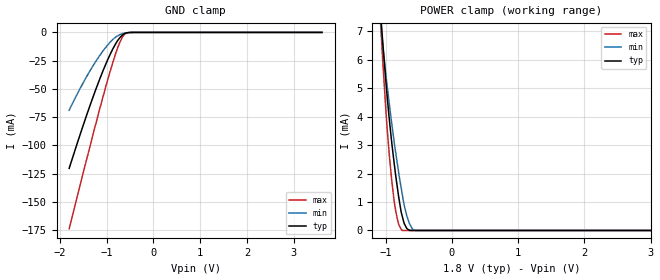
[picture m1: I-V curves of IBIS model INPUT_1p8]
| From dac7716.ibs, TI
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|   input_1p8 Model
[Model]   INPUT_1p8
Model_type   Input
Vinl = 0.2
Vinh = 1.6
|   typ   min   max
|   (nom PVT)   (Fast PVT)   (slow PVT)
|Average
C_comp   3.106e-12   2.398e-12   3.692e-12
[Voltage Range]   1.8   1.7   1.9
|Ambient Temperature   25   105   -40
|Junction Temperature
[Temperature Range]   42   122   -40
[Power Clamp Reference]   1.8   1.7   1.9
[GND Clamp Reference]   0   0   0
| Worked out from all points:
|   GND clamp passes 1 mA (typ) near -0.61 V on its own axis
|   POWER clamp passes 1 mA (typ) near -0.79 V on its own axis
[GND Clamp]
|   Voltage   I(typ)   I(min)   I(max)
-1.8V     -120.4mA   -68.92mA   -173.7mA
-1.581V   -92.27mA   -50.8mA    -137.6mA
-1.392V   -69.11mA   -36.58mA   -106.8mA
-1.231V   -50.47mA   -25.64mA   -80.95mA
-1.071V   -33.33mA   -16.04mA   -56mA
-874.8mV  -15.17mA   -6.608mA   -27.58mA
-764.5mV  -7.199mA   -3.024mA   -13.6mA
-663.8mV  -2.384mA   -1.099mA   -4.149mA
-608.7mV  -920.7uA   -595.9uA   -1.426mA
-546mV    -275.9uA   -244.2uA   -155.3uA
-480.6mV  0A         -160.9uA   0A
3.6V      0A         0A         0A
[POWER Clamp]
|   Voltage   I(typ)   I(min)   I(max)
-1.8V     35.79mA    30.17mA    43.21mA
-1.085V   7.869mA    7.535mA    7.588mA
-1.05V    6.752mA    6.637mA    6.143mA
-983mV    4.836mA    5.181mA    3.724mA
-910.8mV  3.126mA    3.786mA    1.798mA
-842.4mV  1.812mA    2.629mA    600.1uA
-804.4mV  1.187mA    2.034mA    219uA
-751.2mV  510.1uA    1.288mA    0A
-720mV    241.6uA    877.8uA    0A
-642.3mV  7.716uA    248.3uA    0A
-550.8mV  0A         0A         0A
3.6V      0A         0A         0A
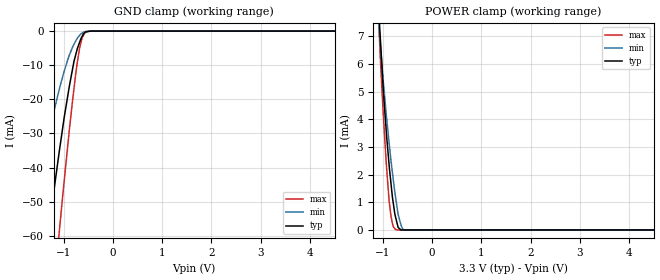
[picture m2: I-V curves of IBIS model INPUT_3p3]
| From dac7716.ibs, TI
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|   input_3p3 Model
[Model]   INPUT_3p3
Model_type   Input
Vinl = 0.6
Vinh = 2.1
|   typ   min   max
|   (nom PVT)   (Fast PVT)   (slow PVT)
|Average
C_comp   2.757e-12   2.145e-12   3.258e-12
[Voltage Range]   3.3   3   3.6
|Ambient Temperature   25   105   -40
|Junction Temperature
[Temperature Range]   42   122   -40
[Power Clamp Reference]   3.3   3   3.6
[GND Clamp Reference]   0   0   0
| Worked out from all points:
|   GND clamp passes 1 mA (typ) near -0.60 V on its own axis
|   POWER clamp passes 1 mA (typ) near -0.79 V on its own axis
[GND Clamp]
|   Voltage   I(typ)   I(min)   I(max)
-3.3V     -325.7mA   -216.2mA   -421.2mA
-1.71V    -108.7mA   -61.27mA   -158.8mA
-1.614V   -96.39mA   -53.51mA   -143mA
-1.34V    -62.93mA   -32.99mA   -98.35mA
-1.29V    -57.27mA   -29.5mA    -90.41mA
-1.092V   -35.57mA   -17.27mA   -59.26mA
-887.7mV  -16.4mA    -7.12mA    -29.36mA
-754.8mV  -6.89mA    -2.912mA   -12.47mA
-675.6mV  -3.238mA   -1.267mA   -4.935mA
-594mV    -727.4uA   -292.2uA   -1.154mA
-463.2mV  -25.21uA   -32.29uA   0A
6.6V      0A         0A         0A
[POWER Clamp]
|   Voltage   I(typ)   I(min)   I(max)
-3.3V     98.4mA     82.08mA    122mA
-1.076V   7.67mA     7.298mA    7.188mA
-1.054V   6.983mA    6.758mA    6.298mA
-996mV    5.198mA    5.464mA    4.313mA
-934.8mV  3.656mA    4.246mA    2.524mA
-873.6mV  2.352mA    3.163mA    1.066mA
-805.2mV  1.172mA    2.064mA    225.3uA
-759mV    604.9uA    1.39mA     48.88uA
-715.2mV  270.7uA    860.8uA    0A
-627mV    0A         150.6uA    0A
-543mV    0A         0A         0A
6.6V      0A         0A         0A
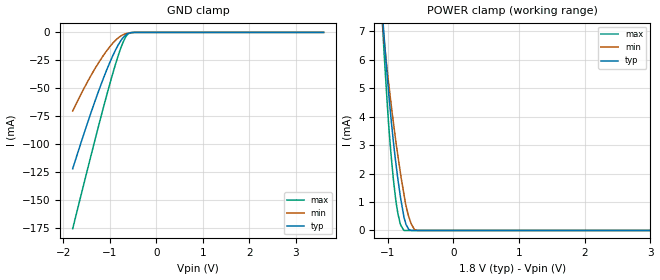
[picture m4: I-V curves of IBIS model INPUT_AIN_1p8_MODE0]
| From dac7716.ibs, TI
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|   input_ain_1p8_mode0 Model
[Model]   INPUT_AIN_1p8_MODE0
Model_type   Input
Vinl = 0.2
Vinh = 1.6
|   typ   min   max
|   (nom PVT)   (Fast PVT)   (slow PVT)
|Average
C_comp   3.175e-12   2.467e-12   3.761e-12
[Voltage Range]   1.8   1.7   1.9
|Ambient Temperature   25   105   -40
|Junction Temperature
[Temperature Range]   42   122   -40
[Power Clamp Reference]   1.8   1.7   1.9
[GND Clamp Reference]   0   0   0
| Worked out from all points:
|   GND clamp passes 1 mA (typ) near -0.61 V on its own axis
|   POWER clamp passes 1 mA (typ) near -0.79 V on its own axis
[GND Clamp]
|   Voltage   I(typ)   I(min)   I(max)
-1.8V     -122mA     -70.37mA   -175.7mA
-1.581V   -93.56mA   -51.97mA   -139.1mA
-1.402V   -71.32mA   -38.27mA   -109.6mA
-1.226V   -50.61mA   -26.04mA   -80.96mA
-1.067V   -33.48mA   -16.39mA   -56.1mA
-882mV    -16.06mA   -7.204mA   -28.95mA
-764.5mV  -7.408mA   -3.214mA   -13.83mA
-661.9mV  -2.445mA   -1.173mA   -4.111mA
-606.8mV  -916.4uA   -640.6uA   -1.426mA
-544.1mV  -240.9uA   -258.5uA   -159.5uA
-466.2mV  0A         0A         0A
3.6V      0A         0A         0A
[POWER Clamp]
|   Voltage   I(typ)   I(min)   I(max)
-1.8V     35.79mA    30.17mA    43.21mA
-1.073V   7.453mA    7.22mA     7.082mA
-1.049V   6.705mA    6.615mA    6.109mA
-983mV    4.848mA    5.181mA    3.724mA
-910.8mV  3.123mA    3.796mA    1.798mA
-842.4mV  1.81mA     2.629mA    600.1uA
-804.4mV  1.197mA    2.034mA    219uA
-751.2mV  486.1uA    1.288mA    0A
-716.4mV  200.3uA    843.9uA    0A
-642.3mV  1.727uA    248.3uA    0A
-543.7mV  0A         0A         0A
3.6V      0A         0A         0A
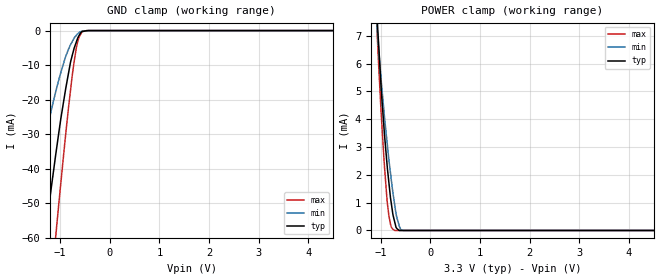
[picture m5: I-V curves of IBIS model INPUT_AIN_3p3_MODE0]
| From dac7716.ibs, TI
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|   input_ain_3p3_mode0 Model
[Model]   INPUT_AIN_3p3_MODE0
Model_type   Input
Vinl = 0.6
Vinh = 2.1
|   typ   min   max
|   (nom PVT)   (Fast PVT)   (slow PVT)
|Average
C_comp   2.821e-12   2.209e-12   3.322e-12
[Voltage Range]   3.3   3   3.6
|Ambient Temperature   25   105   -40
|Junction Temperature
[Temperature Range]   42   122   -40
[Power Clamp Reference]   3.3   3   3.6
[GND Clamp Reference]   0   0   0
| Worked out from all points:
|   GND clamp passes 1 mA (typ) near -0.60 V on its own axis
|   POWER clamp passes 1 mA (typ) near -0.79 V on its own axis
[GND Clamp]
|   Voltage   I(typ)   I(min)   I(max)
-3.3V     -329.7mA   -219.5mA   -426.2mA
-1.704V   -109.5mA   -62.1mA    -159.6mA
-1.607V   -96.89mA   -54.17mA   -143.5mA
-1.284V   -57.42mA   -29.91mA   -90.33mA
-1.092V   -36.12mA   -17.84mA   -59.93mA
-1.068V   -33.64mA   -16.42mA   -56.15mA
-887.7mV  -16.69mA   -7.449mA   -29.8mA
-754.8mV  -7.061mA   -3.116mA   -12.69mA
-675.6mV  -3.33mA    -1.382mA   -5.06mA
-591mV    -733.5uA   -327.4uA   -1.128mA
-463.2mV  -29.3uA    -42.59uA   0A
6.6V      0A         0A         0A
[POWER Clamp]
|   Voltage   I(typ)   I(min)   I(max)
-3.3V     98.4mA     82.08mA    122mA
-1.076V   7.67mA     7.298mA    7.188mA
-1.054V   6.983mA    6.758mA    6.299mA
-992.4mV  5.087mA    5.388mA    4.199mA
-934.8mV  3.651mA    4.246mA    2.524mA
-873.6mV  2.352mA    3.163mA    1.066mA
-805.2mV  1.172mA    2.064mA    225.5uA
-759mV    604.9uA    1.39mA     48.9uA
-715.2mV  270.8uA    860.8uA    0A
-627mV    0A         150.6uA    0A
-543mV    0A         0A         0A
6.6V      0A         0A         0A
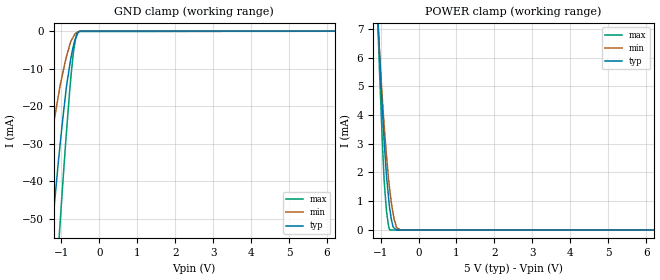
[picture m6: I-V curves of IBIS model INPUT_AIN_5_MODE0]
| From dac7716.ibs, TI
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|   input_ain_5_mode0 Model
[Model]   INPUT_AIN_5_MODE0
Model_type   Input
Vinl = 0.6
Vinh = 2.5
|   typ   min   max
|   (nom PVT)   (Fast PVT)   (slow PVT)
|Average
C_comp   2.565e-12   2.031e-12   2.996e-12
[Voltage Range]   5   4.5   5.5
|Ambient Temperature   25   105   -40
|Junction Temperature
[Temperature Range]   42   122   -40
[Power Clamp Reference]   5   4.5   5.5
[GND Clamp Reference]   0   0   0
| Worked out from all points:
|   GND clamp passes 1 mA (typ) near -0.60 V on its own axis
|   POWER clamp passes 1 mA (typ) near -0.78 V on its own axis
[GND Clamp]
|   Voltage   I(typ)   I(min)   I(max)
-5V       -570.9mA   -406.5mA   -709.4mA
-1.607V   -96.93mA   -54.15mA   -143.3mA
-1.288V   -57.83mA   -30.16mA   -90.88mA
-1.23V    -51.12mA   -26.34mA   -81.78mA
-1.065V   -33.25mA   -16.36mA   -55.76mA
-1.036V   -30.38mA   -14.6mA    -51.34mA
-865mV    -14.67mA   -6.731mA   -26.69mA
-781.5mV  -9.162mA   -3.755mA   -15.87mA
-688mV    -4.174mA   -1.571mA   -6.04mA
-622mV    -1.645mA   -591.1uA   -2.016mA
-527mV    -80.75uA   0A         -167.1uA
10V       0A         0A         0A
[POWER Clamp]
|   Voltage   I(typ)   I(min)   I(max)
-5V       170.1mA    141.7mA    212mA
-1.07V    7.376mA    7.216mA    7.083mA
-1.065V   7.224mA    7.085mA    6.895mA
-1.036V   6.39mA     6.309mA    5.781mA
-957.5mV  4.282mA    4.628mA    3.177mA
-908mV    3.121mA    3.669mA    1.756mA
-842mV    1.844mA    2.546mA    630.8uA
-760mV    749.3uA    1.414mA    1.477uA
-644mV    69.28uA    382.5uA    0A
-581mV    0A         86.68uA    0A
-480mV    0A         3.528uA    0A
10V       0A         0A         0A
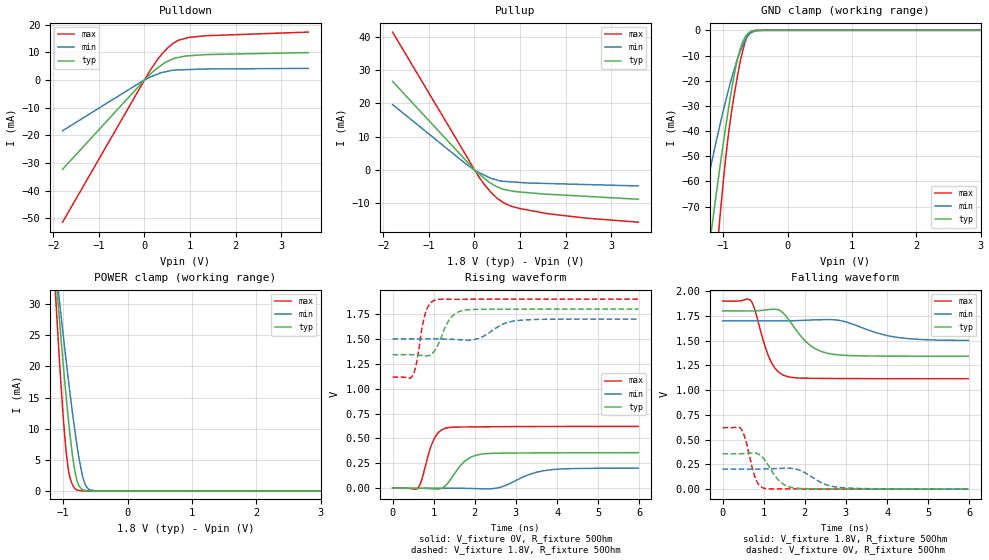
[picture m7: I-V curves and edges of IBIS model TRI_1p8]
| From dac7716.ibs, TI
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|   tri_1p8 Model
[Model]   TRI_1p8
Model_type   3-state
Polarity   Non-Inverting
Enable   Active-Low
Vmeas = 0.9
Vref = 0.9
Cref = 15pF
Rref = 50
|   typ   min   max
|   (nom PVT)   (Fast PVT)   (slow PVT)
|Average
C_comp   4.133e-12   3.096e-12   5.197e-12
|ON state : BUFFER OUTPUT TURNED HIGH
|C_comp   4.274e-12   3.226e-12   5.365e-12
|OFF state: BUFFER in HIGH IMPEDANCE for IOs and 3-state,
|This is BUFFER in LOW state for OUTPUT only type
|C_comp   3.992e-12   2.966e-12   5.030e-12
| Where nom  PVT is Nominal Process, 1.8V, 42C
|   Fast PVT is Strong Process,  1.9V, -40C
|   Slow PVT is Weak Process,   1.7V, 122C
[Voltage Range]   1.8   1.7   1.9
|Ambient Temperature   25   105   -40
|Junction Temperature
[Temperature Range]   42   122   -40
[Pullup Reference]   1.8   1.7   1.9
[Pulldown Reference]   0   0   0
[Power Clamp Reference]   1.8   1.7   1.9
[GND Clamp Reference]   0   0   0
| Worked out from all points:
|   slope of the pulldown table from 0 to 0.27 V, typ, clamps not added: 65.2 ohm
|   slope of the pullup table from 0 to 0.27 V, typ, clamps not added: 86.7 ohm
|   GND clamp passes 1 mA (typ) near -0.60 V on its own axis
|   POWER clamp passes 1 mA (typ) near -0.76 V on its own axis
|   falling waveform, V_fixture 1.8V, R_fixture 50Ohm: 20-80 % time 580ps typ, 914ps min, 365ps max; typ from 1.8 V to 1.34 V
|   rising waveform, V_fixture 0V, R_fixture 50Ohm: 20-80 % time 421ps typ, 694ps min, 275ps max; typ from 0 V to 0.357 V
|   rising waveform, V_fixture 1.8V, R_fixture 50Ohm: 20-80 % time 315ps typ, 489ps min, 199ps max; typ from 1.34 V to 1.8 V
|   falling waveform, V_fixture 0V, R_fixture 50Ohm: 20-80 % time 370ps typ, 526ps min, 225ps max; typ from 0.358 V to 0 V
[Pulldown]
|   Voltage   I(typ)   I(min)   I(max)
-1.8V     -32.27mA   -18.33mA   -51.39mA
-81.3mV   -1.487mA   -777.8uA   -2.343mA
103.8mV   1.762mA    866.5uA    2.939mA
276.7mV   4.221mA    2.067mA    7.199mA
394.5mV   5.632mA    2.734mA    9.621mA
622.5mV   7.619mA    3.503mA    13.16mA
738.4mV   8.142mA    3.633mA    14.31mA
964.5mV   8.753mA    3.765mA    15.38mA
1.343V    9.171mA    3.971mA    16mA
3.6V      9.904mA    4.213mA    17.32mA
[GND Clamp]
|   Voltage   I(typ)   I(min)   I(max)
-1.8V     -210.1mA   -135.7mA   -307.4mA
-1.365V   -116.4mA   -75.64mA   -169.4mA
-1.179V   -78.73mA   -52.45mA   -112mA
-1.103V   -64.09mA   -43.55mA   -89.38mA
-1.05V    -54.37mA   -37.59mA   -74.37mA
-952.6mV  -37.05mA   -27.23mA   -48.83mA
-912.7mV  -30.4mA    -23.21mA   -40.25mA
-823.4mV  -17.14mA   -15.09mA   -24.94mA
-734.4mV  -7.311mA   -8.279mA   -12.33mA
-669.5mV  -3.293mA   -4.463mA   -5.457mA
-576mV    -525.2uA   -1.11mA    -721.3uA
3.6V      0A         0A         0A
[Pullup]
|   Voltage   I(typ)   I(min)   I(max)
-1.8V     26.58mA    19.62mA    41.39mA
-198.6mV  2.985mA    1.913mA    4.682mA
0V        0A         0A         0A
229.2mV   -2.659mA   -1.66mA    -4.6mA
327.6mV   -3.759mA   -2.325mA   -6.182mA
497.1mV   -5.062mA   -3.039mA   -8.497mA
632mV     -5.816mA   -3.419mA   -9.816mA
772.6mV   -6.209mA   -3.552mA   -10.74mA
960.7mV   -6.573mA   -3.73mA    -11.49mA
1.603V    -7.289mA   -4.076mA   -13.13mA
2.452V    -7.934mA   -4.388mA   -14.48mA
3.6V      -8.805mA   -4.808mA   -15.69mA
[POWER Clamp]
|   Voltage   I(typ)   I(min)   I(max)
-1.8V     121.3mA    102.9mA    147.5mA
-1.116V   34.95mA    36.2mA     31.06mA
-1.101V   33.05mA    34.73mA    28.51mA
-1.069V   28.89mA    31.59mA    22.82mA
-1.008V   21.41mA    25.82mA    13.15mA
-946.9mV  14.43mA    20.31mA    5.667mA
-891.8mV  8.882mA    15.58mA    2.05mA
-829.8mV  3.887mA    10.59mA    551.5uA
-793mV    2.005mA    7.875mA    162.1uA
-695mV    148.3uA    2.221mA    0A
-598.1mV  14.25uA    199uA      0A
3.6V      0A         0A         0A
[Ramp]
R_load = 50
|   typ   min   max
dV/dt_r   0.214292/4.20846e-10   0.120795/6.91611e-10   0.372353/2.74618e-10
dV/dt_f   0.274822/5.79819e-10   0.118917/9.1338e-10   0.470715/3.64574e-10
[Falling Waveform]
V_fixture = 1.8V
V_fixture_min = 1.7V
V_fixture_max = 1.9V
R_fixture = 50Ohm
C_fixture = 0F
|   Time   V(typ)   V(min)   V(max)
0s        1.8V       1.7V       1.9V
700ps     1.799V     1.7V       1.897V
1.15ns    1.814V     1.7V       1.312V
1.325ns   1.815V     1.7V       1.197V
1.55ns    1.743V     1.7V       1.141V
2.05ns    1.481V     1.707V     1.12V
2.5ns     1.378V     1.712V     1.118V
2.95ns    1.352V     1.694V     1.117V
4.25ns    1.343V     1.533V     1.116V
5.975ns   1.342V     1.502V     1.115V
[Rising Waveform]
V_fixture = 0V
V_fixture_min = 0V
V_fixture_max = 0V
R_fixture = 50Ohm
C_fixture = 0F
|   Time   V(typ)   V(min)   V(max)
0s        755.7pV    1.323nV    611.1pV
600ps     466.8uV    1.212uV    -6.279mV
700ps     280.4uV    26.68uV    72.97mV
1ns       -6.947mV   139.5uV    487.1mV
1.325ns   42.76mV    335.5uV    606.5mV
1.75ns    268.7mV    -782.1uV   615mV
2.15ns    341.6mV    -5.14mV    616.6mV
2.6ns     352mV      7.458mV    618.2mV
3.775ns   355.1mV    181.8mV    620mV
5.975ns   357.2mV    201.3mV    620.6mV
[Rising Waveform]
V_fixture = 1.8V
V_fixture_min = 1.7V
V_fixture_max = 1.9V
R_fixture = 50Ohm
C_fixture = 0F
|   Time   V(typ)   V(min)   V(max)
0s        1.341V     1.5V       1.115V
500ps     1.341V     1.5V       1.139V
575ps     1.339V     1.5V       1.243V
700ps     1.334V     1.5V       1.575V
800ps     1.329V     1.5V       1.76V
1.025ns   1.383V     1.5V       1.889V
1.375ns   1.688V     1.497V     1.898V
1.7ns     1.784V     1.49V      1.898V
3.025ns   1.798V     1.684V     1.9V
5.975ns   1.8V       1.699V     1.9V
[Falling Waveform]
|Gnd
V_fixture = 0V
V_fixture_min = 0V
V_fixture_max = 0V
R_fixture = 50Ohm
C_fixture = 0F
|   Time   V(typ)   V(min)   V(max)
0s        358.1mV    203.4mV    620.6mV
450ps     358.1mV    203.1mV    608.4mV
550ps     359.8mV    203mV      512.4mV
800ps     364.6mV    203mV      108mV
900ps     348.4mV    203.3mV    35.81mV
1.025ns   295.1mV    204.1mV    7.141mV
1.4ns     75.37mV    209.4mV    3.13mV
1.75ns    11.94mV    205.8mV    2.272mV
2.8ns     2.345mV    19.79mV    748.6uV
5.975ns   447.4uV    1.122mV    28.86uV
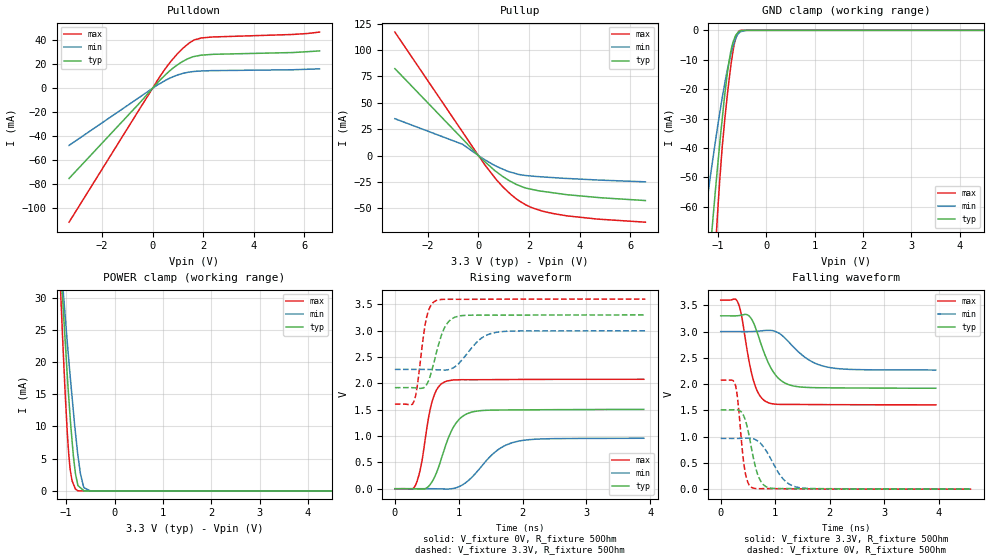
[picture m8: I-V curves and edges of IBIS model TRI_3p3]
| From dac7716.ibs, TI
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|   tri_3p3 Model
[Model]   TRI_3p3
Model_type   3-state
Polarity   Non-Inverting
Enable   Active-Low
Vmeas = 1.65
Vref = 1.65
Cref = 15pF
Rref = 50
|   typ   min   max
|   (nom PVT)   (Fast PVT)   (slow PVT)
|Average
C_comp   3.777e-12   2.887e-12   4.746e-12
|ON state : BUFFER OUTPUT TURNED HIGH
|C_comp   4.008e-12   3.131e-12   5.011e-12
|OFF state: BUFFER in HIGH IMPEDANCE for IOs and 3-state,
|This is BUFFER in LOW state for OUTPUT only type
|C_comp   3.547e-12   2.644e-12   4.482e-12
| Where nom  PVT is Nominal Process, 3.3V, 42C
|   Fast PVT is Strong Process,  3.6V, -40C
|   Slow PVT is Weak Process,   3V, 122C
[Voltage Range]   3.3   3   3.6
|Ambient Temperature   25   105   -40
|Junction Temperature
[Temperature Range]   42   122   -40
[Pullup Reference]   3.3   3   3.6
[Pulldown Reference]   0   0   0
[Power Clamp Reference]   3.3   3   3.6
[GND Clamp Reference]   0   0   0
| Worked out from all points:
|   slope of the pulldown table from 0 to 0.495 V, typ, clamps not added: 45.2 ohm
|   slope of the pullup table from 0 to 0.495 V, typ, clamps not added: 45.2 ohm
|   GND clamp passes 1 mA (typ) near -0.60 V on its own axis
|   POWER clamp passes 1 mA (typ) near -0.76 V on its own axis
|   falling waveform, V_fixture 3.3V, R_fixture 50Ohm: 20-80 % time 334ps typ, 496ps min, 220ps max; typ from 3.3 V to 1.92 V
|   rising waveform, V_fixture 0V, R_fixture 50Ohm: 20-80 % time 284ps typ, 465ps min, 179ps max; typ from 0 V to 1.51 V
|   rising waveform, V_fixture 3.3V, R_fixture 50Ohm: 20-80 % time 199ps typ, 322ps min, 131ps max; typ from 1.92 V to 3.3 V
|   falling waveform, V_fixture 0V, R_fixture 50Ohm: 20-80 % time 190ps typ, 338ps min, 118ps max; typ from 1.51 V to 0.002 V
[Pulldown]
|   Voltage   I(typ)   I(min)   I(max)
-3.3V     -75.2mA    -47.61mA   -111.7mA
-455.4mV  -10.96mA   -6.595mA   -15.32mA
278.4mV   6.559mA    3.789mA    9.458mA
660mV     14.3mA     8.266mA    20.78mA
966mV     19.31mA    10.95mA    28.44mA
1.463V    25.24mA    13.61mA    38mA
1.668V    26.65mA    14.12mA    40.52mA
1.938V    27.68mA    14.47mA    42.02mA
2.345V    28.29mA    14.75mA    42.8mA
5.524V    29.83mA    15.47mA    44.9mA
6.6V      31.19mA    16.23mA    46.9mA
[GND Clamp]
|   Voltage   I(typ)   I(min)   I(max)
-3.3V     -553.3mA   -373.7mA   -789.2mA
-1.287V   -100.3mA   -65.67mA   -145.1mA
-1.129V   -69.21mA   -46.61mA   -97.18mA
-1.053V   -54.76mA   -38mA      -75.08mA
-1.014V   -47.77mA   -33.64mA   -64.35mA
-960mV    -38.3mA    -27.96mA   -50.6mA
-906mV    -29.46mA   -22.56mA   -38.93mA
-805.2mV  -14.72mA   -13.54mA   -22.17mA
-749.1mV  -8.599mA   -9.385mA   -14.4mA
-654mV    -2.621mA   -3.71mA    -4.227mA
-534mV    -167.2uA   -473.8uA   0A
6.6V      0A         0A         0A
[Pullup]
|   Voltage   I(typ)   I(min)   I(max)
-3.3V     82.39mA    34.91mA    117mA
-624mV    15.67mA    10.64mA    22.25mA
246mV     -5.601mA   -3.884mA   -8.554mA
706.8mV   -15.31mA   -10.15mA   -22.76mA
937.2mV   -19.47mA   -12.6mA    -28.91mA
1.492V    -27.29mA   -17.18mA   -40.92mA
1.877V    -30.81mA   -18.95mA   -46.8mA
2.082V    -31.89mA   -19.43mA   -49.09mA
2.942V    -35.27mA   -20.9mA    -54.94mA
3.511V    -37.14mA   -21.73mA   -57.18mA
4.71V     -39.72mA   -23.18mA   -60.23mA
6.6V      -42.65mA   -24.91mA   -63.15mA
[POWER Clamp]
|   Voltage   I(typ)   I(min)   I(max)
-3.3V     229.9mA    197mA      273.8mA
-1.122V   35.76mA    36.81mA    32.12mA
-1.105V   33.62mA    35.19mA    29.24mA
-1.068V   29.02mA    31.52mA    22.71mA
-1.025V   23.73mA    27.48mA    15.71mA
-978mV    18mA       23.11mA    9.112mA
-924mV    12.02mA    18.32mA    3.777mA
-848.1mV  5.177mA    12.07mA    1.005mA
-762mV    1.001mA    5.751mA    27.81uA
-645mV    106.7uA    766.7uA    0A
-498mV    0A         0A         0A
6.6V      0A         0A         0A
[Ramp]
R_load = 50
|   typ   min   max
dV/dt_r   0.905231/2.85134e-10   0.577319/4.68406e-10   1.24661/1.7929e-10
dV/dt_f   0.82846/3.34764e-10   0.440217/4.99176e-10   1.1967/2.20221e-10
[Falling Waveform]
V_fixture = 3.3V
V_fixture_min = 3V
V_fixture_max = 3.6V
R_fixture = 50Ohm
C_fixture = 0F
|   Time   V(typ)   V(min)   V(max)
0s        3.3V       3V         3.6V
325ps     3.303V     3V         3.531V
375ps     3.312V     3V         3.348V
500ps     3.313V     3V         2.552V
600ps     3.173V     3.002V     2.074V
825ps     2.523V     3.022V     1.67V
1.05ns    2.121V     2.981V     1.615V
1.35ns    1.962V     2.693V     1.613V
2.05ns    1.929V     2.308V     1.609V
3.95ns    1.921V     2.268V     1.606V
[Rising Waveform]
V_fixture = 0V
V_fixture_min = 0V
V_fixture_max = 0V
R_fixture = 50Ohm
C_fixture = 0F
|   Time   V(typ)   V(min)   V(max)
0s        1.178nV    1.774nV    1.033nV
325ps     -1.201mV   207.6uV    71.59mV
425ps     -7.557mV   423.9uV    529.8mV
575ps     117.8mV    -60.84uV   1.619V
800ps     840.1mV    -6.055mV   2.038V
950ps     1.232V     13.89mV    2.067V
1.125ns   1.42V      128.9mV    2.069V
1.575ns   1.493V     701.6mV    2.071V
1.875ns   1.496V     885.7mV    2.073V
3.9ns     1.506V     958mV      2.077V
[Rising Waveform]
V_fixture = 3.3V
V_fixture_min = 3V
V_fixture_max = 3.6V
R_fixture = 50Ohm
C_fixture = 0F
|   Time   V(typ)   V(min)   V(max)
0s        1.918V     2.264V     1.605V
300ps     1.916V     2.265V     1.66V
350ps     1.91V      2.265V     1.941V
500ps     1.981V     2.264V     3.271V
650ps     2.584V     2.258V     3.574V
800ps     3.103V     2.253V     3.596V
1.025ns   3.282V     2.408V     3.595V
1.325ns   3.295V     2.829V     3.596V
1.6ns     3.295V     2.971V     3.598V
3.925ns   3.299V     2.998V     3.6V
[Falling Waveform]
|Gnd
V_fixture = 0V
V_fixture_min = 0V
V_fixture_max = 0V
R_fixture = 50Ohm
C_fixture = 0F
|   Time   V(typ)   V(min)   V(max)
0s        1.509V     966.2mV    2.075V
225ps     1.51V      965.5mV    2.069V
275ps     1.512V     965.8mV    1.965V
450ps     1.323V     971.6mV    313.6mV
575ps     717.8mV    966.6mV    29.98mV
675ps     291.4mV    920.9mV    9.944mV
800ps     70.95mV    784.4mV    10.54mV
1.125ns   11.05mV    220.1mV    8.29mV
1.4ns     10.59mV    38.09mV    5.916mV
4.6ns     1.794mV    3.826mV    175.5uV
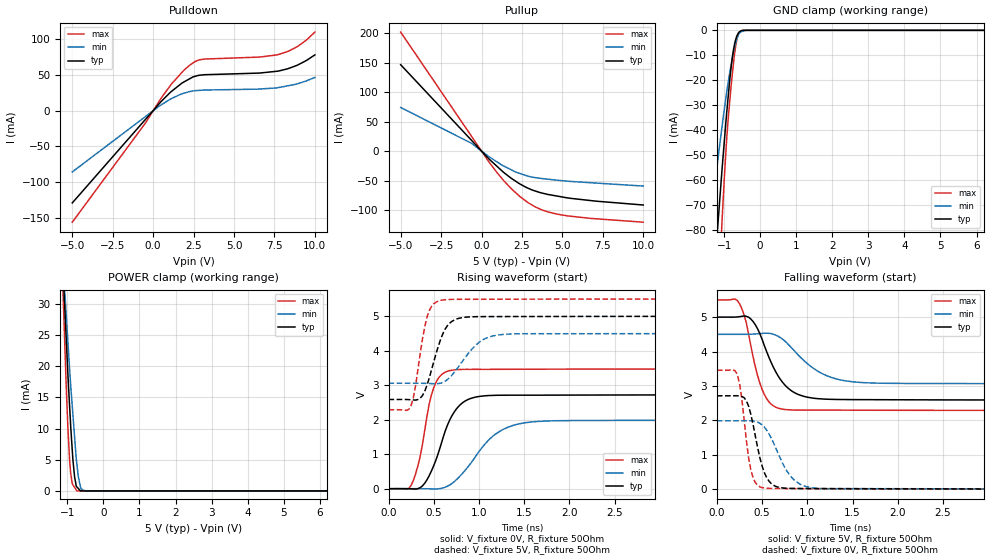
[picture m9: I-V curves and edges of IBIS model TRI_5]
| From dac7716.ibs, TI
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|   tri_5 Model
[Model]   TRI_5
Model_type   3-state
Polarity   Non-Inverting
Enable   Active-Low
Vmeas = 2.5
Vref = 2.5
Cref = 15pF
Rref = 50
|   typ   min   max
|   (nom PVT)   (Fast PVT)   (slow PVT)
|Average
C_comp   3.512e-12   2.849e-12   4.317e-12
|ON state : BUFFER OUTPUT TURNED HIGH
|C_comp   3.797e-12   3.276e-12   4.566e-12
|OFF state: BUFFER in HIGH IMPEDANCE for IOs and 3-state,
|This is BUFFER in LOW state for OUTPUT only type
|C_comp   3.227e-12   2.422e-12   4.067e-12
| Where nom  PVT is Nominal Process, 5V, 42C
|   Fast PVT is Strong Process,  5.5V, -40C
|   Slow PVT is Weak Process,   4.5V, 122C
[Voltage Range]   5   4.5   5.5
|Ambient Temperature   25   105   -40
|Junction Temperature
[Temperature Range]   42   122   -40
[Pullup Reference]   5   4.5   5.5
[Pulldown Reference]   0   0   0
[Power Clamp Reference]   5   4.5   5.5
[GND Clamp Reference]   0   0   0
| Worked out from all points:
|   slope of the pulldown table from 0 to 0.75 V, typ, clamps not added: 40.3 ohm
|   slope of the pullup table from 0 to 0.75 V, typ, clamps not added: 36.4 ohm
|   GND clamp passes 1 mA (typ) near -0.60 V on its own axis
|   POWER clamp passes 1 mA (typ) near -0.76 V on its own axis
|   falling waveform, V_fixture 5V, R_fixture 50Ohm: 20-80 % time 262ps typ, 382ps min, 173ps max; typ from 5 V to 2.59 V
|   rising waveform, V_fixture 0V, R_fixture 50Ohm: 20-80 % time 236ps typ, 385ps min, 154ps max; typ from 0 V to 2.72 V
|   rising waveform, V_fixture 5V, R_fixture 50Ohm: 20-80 % time 171ps typ, 267ps min, 120ps max; typ from 2.59 V to 5 V
|   falling waveform, V_fixture 0V, R_fixture 50Ohm: 20-80 % time 141ps typ, 228ps min, 98.6ps max; typ from 2.71 V to 0.003 V
[Pulldown]
|   Voltage   I(typ)   I(min)   I(max)
-5V       -129mA     -85.64mA   -155.9mA
-457mV    -11.67mA   -7.881mA   -16.6mA
500mV     13.01mA    8.146mA    17.8mA
1.138V    27.1mA     17.05mA    37.53mA
1.79V     38.82mA    23.61mA    53.86mA
2.232V    44.37mA    26.68mA    63.19mA
2.574V    47.99mA    28.02mA    68.59mA
3.217V    50.4mA     28.96mA    72.33mA
6.588V    52.69mA    30.36mA    75.04mA
7.766V    55.59mA    32.48mA    78.76mA
8.926V    63.84mA    37.7mA     89.81mA
10V       78.11mA    46.56mA    110mA
[GND Clamp]
|   Voltage   I(typ)   I(min)   I(max)
-5V       -949mA     -662mA     -1.336A
-1.373V   -118.1mA   -76.66mA   -172.2mA
-1.179V   -78.96mA   -52.49mA   -112.3mA
-1.06V    -56.1mA    -38.8mA    -77.1mA
-996mV    -44.73mA   -31.79mA   -59.57mA
-924.5mV  -32.36mA   -24.4mA    -42.65mA
-803.5mV  -14.52mA   -13.58mA   -21.92mA
-740mV    -7.777mA   -8.687mA   -13.12mA
-660.5mV  -2.871mA   -4.083mA   -4.777mA
-594.5mV  -839.4uA   -1.553mA   -1.119mA
-520mV    -102uA     -529.4uA   -212.2uA
10V       0A         0A         0A
[Pullup]
|   Voltage   I(typ)   I(min)   I(max)
-5V       146.5mA    74mA       201.8mA
-617mV    18.24mA    13.22mA    25.04mA
533mV     -15.17mA   -10.72mA   -21.14mA
1.413V    -37.08mA   -25.89mA   -51.34mA
2.37V     -55.65mA   -37.93mA   -76.98mA
2.843V    -62.52mA   -42.35mA   -86.76mA
3.333V    -67.78mA   -45.05mA   -94.79mA
4.163V    -73.78mA   -47.84mA   -103.6mA
4.702V    -76.4mA    -49.46mA   -107mA
6.748V    -83.88mA   -53.62mA   -114.1mA
10V       -91.42mA   -59.29mA   -120.6mA
[POWER Clamp]
|   Voltage   I(typ)   I(min)   I(max)
-5V       299.3mA    258.6mA    355.5mA
-1.123V   35.84mA    36.91mA    32.21mA
-1.081V   30.43mA    32.74mA    25.07mA
-1.034V   24.78mA    28.47mA    17.26mA
-985mV    18.7mA     23.89mA    10.06mA
-935.5mV  13.34mA    19.32mA    4.74mA
-845mV    4.932mA    12.13mA    970.2uA
-800mV    2.265mA    8.705mA    573.7uA
-732mV    612.6uA    4.095mA    0A
-635mV    22.6uA     589.3uA    0A
-486.5mV  0A         0A         0A
10V       0A         0A         0A
[Ramp]
R_load = 50
|   typ   min   max
dV/dt_r   1.6336/2.36311e-10   1.1929/3.86042e-10   2.08208/1.53826e-10
dV/dt_f   1.44734/2.62271e-10   0.862843/3.8351e-10   1.92647/1.73059e-10
[Falling Waveform]
V_fixture = 5V
V_fixture_min = 4.5V
V_fixture_max = 5.5V
R_fixture = 50Ohm
C_fixture = 0F
|   Time   V(typ)   V(min)   V(max)
0s        5V         4.5V       5.5V
250ps     5.012V     4.499V     5.389V
325ps     5.024V     4.5V       4.834V
375ps     4.946V     4.504V     4.17V
500ps     4.353V     4.527V     2.899V
675ps     3.298V     4.446V     2.356V
925ps     2.727V     3.83V      2.299V
1.15ns    2.624V     3.377V     2.299V
1.4ns     2.605V     3.158V     2.297V
3.725ns   2.59V      3.065V     2.289V
[Rising Waveform]
V_fixture = 0V
V_fixture_min = 0V
V_fixture_max = 0V
R_fixture = 50Ohm
C_fixture = 0F
|   Time   V(typ)   V(min)   V(max)
0s        1.687nV    2.376nV    1.528nV
250ps     -3.858mV   600.7uV    98.48mV
350ps     28.59mV    57.07uV    938.1mV
475ps     518.7mV    -4.867mV   2.725V
550ps     1.028V     -3.398mV   3.201V
650ps     1.833V     68.9mV     3.405V
900ps     2.61V      706.2mV    3.461V
1.15ns    2.705V     1.515V     3.462V
1.425ns   2.712V     1.869V     3.464V
3.875ns   2.721V     1.985V     3.47V
[Rising Waveform]
V_fixture = 5V
V_fixture_min = 4.5V
V_fixture_max = 5.5V
R_fixture = 50Ohm
C_fixture = 0F
|   Time   V(typ)   V(min)   V(max)
0s        2.587V     3.06V      2.289V
250ps     2.579V     3.061V     2.419V
350ps     2.623V     3.059V     3.92V
425ps     2.999V     3.053V     4.972V
550ps     4.128V     3.048V     5.444V
625ps     4.625V     3.115V     5.481V
725ps     4.888V     3.37V      5.492V
975ps     4.989V     4.187V     5.494V
1.2ns     4.992V     4.451V     5.495V
4.3ns     4.999V     4.498V     5.5V
[Falling Waveform]
|Gnd
V_fixture = 0V
V_fixture_min = 0V
V_fixture_max = 0V
R_fixture = 50Ohm
C_fixture = 0F
|   Time   V(typ)   V(min)   V(max)
0s        2.714V     1.987V     3.456V
225ps     2.714V     1.987V     3.339V
275ps     2.694V     1.989V     2.631V
375ps     2.177V     1.985V     565.1mV
425ps     1.543V     1.965V     191.1mV
500ps     671mV      1.866V     45.2mV
650ps     81.08mV    1.201V     20.33mV
825ps     22.26mV    344.6mV    16.73mV
1.025ns   19.66mV    51.71mV    12.82mV
4.05ns    3.232mV    6.928mV    381.6uV
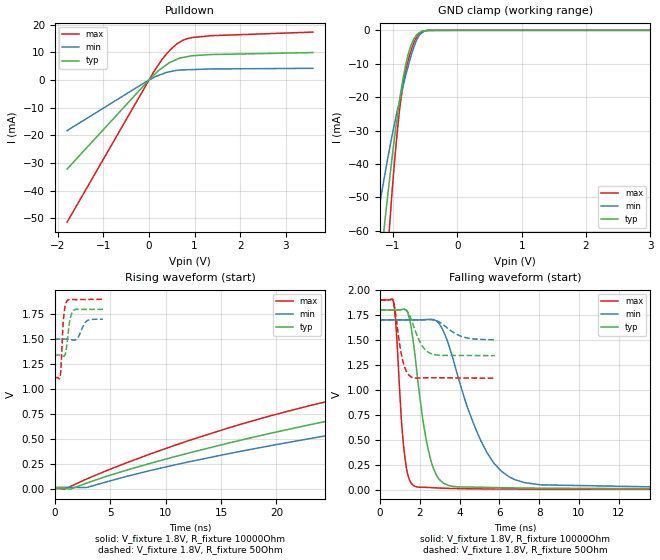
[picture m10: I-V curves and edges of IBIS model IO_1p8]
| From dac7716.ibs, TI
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|   io_1p8 Model
[Model]   IO_1p8
Model_type   I/O_open_drain
Polarity   Non-Inverting
Enable   Active-Low
Vinl = 0.2
Vinh = 1.6
Vmeas = 0.9
Vref = 1.8
Cref = 15pF
Rref = 10000
|   typ   min   max
|   (nom PVT)   (Fast PVT)   (slow PVT)
|Average
C_comp   5.722e-12   4.533e-12   6.777e-12
|ON state : BUFFER OUTPUT TURNED HIGH
|C_comp   5.980e-12   4.767e-12   6.989e-12
|OFF state: BUFFER in HIGH IMPEDANCE for IOs and 3-state,
|This is BUFFER in LOW state for OUTPUT only type
|C_comp   5.463e-12   4.299e-12   6.564e-12
| Where nom  PVT is Nominal Process, 1.8V, 42C
|   Fast PVT is Strong Process,  1.9V, -40C
|   Slow PVT is Weak Process,   1.7V, 122C
[Voltage Range]   1.8   1.7   1.9
|Ambient Temperature   25   105   -40
|Junction Temperature
[Temperature Range]   42   122   -40
[Pullup Reference]   1.8   1.7   1.9
[Pulldown Reference]   0   0   0
[Power Clamp Reference]   1.8   1.7   1.9
[GND Clamp Reference]   0   0   0
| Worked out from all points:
|   slope of the pulldown table from 0 to 0.27 V, typ, clamps not added: 65.1 ohm
|   GND clamp passes 1 mA (typ) near -0.61 V on its own axis
|   falling waveform, V_fixture 1.8V, R_fixture 10000Ohm: 20-80 % time 767ps typ, 1.85ns min, 374ps max; typ from 1.8 V to 0.01 V
|   rising waveform, V_fixture 1.8V, R_fixture 10000Ohm: 20-80 % time 83.6ns typ, 97.6ns min, 64ns max; typ from 0.01 V to 1.8 V
|   falling waveform, V_fixture 1.8V, R_fixture 50Ohm: 20-80 % time 581ps typ, 898ps min, 372ps max; typ from 1.8 V to 1.34 V
|   rising waveform, V_fixture 1.8V, R_fixture 50Ohm: 20-80 % time 315ps typ, 478ps min, 232ps max; typ from 1.34 V to 1.8 V
[Pulldown]
|   Voltage   I(typ)   I(min)   I(max)
-1.8V     -32.23mA   -18.32mA   -51.44mA
103.8mV   1.723mA    870.5uA    2.937mA
278.6mV   4.248mA    2.076mA    7.241mA
396.4mV   5.654mA    2.776mA    9.657mA
624.4mV   7.557mA    3.5mA      13.18mA
734.6mV   8.12mA     3.63mA     14.28mA
844.8mV   8.454mA    3.693mA    14.96mA
1.354V    9.185mA    3.973mA    16.01mA
3.6V      9.904mA    4.213mA    17.32mA
[GND Clamp]
|   Voltage   I(typ)   I(min)   I(max)
-1.8V     -193.8mA   -129.1mA   -288.5mA
-1.278V   -85.84mA   -60.59mA   -124.4mA
-1.241V   -78.81mA   -56.2mA    -113.3mA
-1.13V    -58.33mA   -43.79mA   -80.68mA
-1.061V   -46.19mA   -36.38mA   -61.19mA
-929.8mV  -25.6mA    -23.9mA    -30mA
-867.1mV  -17.28mA   -18.73mA   -19.54mA
-798.7mV  -10.21mA   -13.39mA   -12mA
-725.4mV  -4.807mA   -8.133mA   -6.64mA
-592.2mV  -691uA     -1.601mA   -991.9uA
-416.2mV  -29.53uA   0A         -27.2uA
3.6V      0A         0A         0A
[POWER Clamp]
|   Voltage   I(typ)   I(min)   I(max)
-1.8V     0A         0A         0A
3.6V      0A         0A         0A
[Ramp]
R_load = 10000
|   typ   min   max
dV/dt_r   1.07406/8.36788e-08   1.00883/9.86698e-08   1.13617/6.38714e-08
dV/dt_f   1.07407/7.64431e-10   1.00907/1.83733e-09   1.13617/3.74083e-10
[Falling Waveform]
V_fixture = 1.8V
V_fixture_min = 1.7V
V_fixture_max = 1.9V
R_fixture = 10000Ohm
C_fixture = 0F
|   Time   V(typ)   V(min)   V(max)
0s        1.8V       1.7V       1.9V
675ps     1.8V       1.7V       1.885V
1.25ns    1.807V     1.7V       327mV
1.55ns    1.646V     1.7V       72.44mV
1.9ns     1.093V     1.7V       27.44mV
2.375ns   449.4mV    1.705V     23.93mV
3ns       100.8mV    1.654V     17.63mV
5.375ns   24.29mV    373.5mV    8.768mV
7.25ns    18.16mV    72.81mV    7.29mV
44.62ns   10.18mV    18.43mV    6.562mV
[Rising Waveform]
V_fixture = 1.8V
V_fixture_min = 1.7V
V_fixture_max = 1.9V
R_fixture = 10000Ohm
C_fixture = 0F
|   Time   V(typ)   V(min)   V(max)
0s        9.883mV    18.21mV    6.383mV
2.875ns   60.94mV    16.09mV    101.9mV
19.58ns   561.3mV    437mV      736.7mV
27.72ns   748.9mV    593.7mV    951.6mV
38.27ns   945.2mV    769.8mV    1.143V
66.3ns    1.248V     1.098V     1.463V
109.7ns   1.509V     1.345V     1.711V
163.1ns   1.665V     1.51V      1.823V
238.6ns   1.745V     1.613V     1.877V
602.2ns   1.799V     1.694V     1.9V
[Falling Waveform]
V_fixture = 1.8V
V_fixture_min = 1.7V
V_fixture_max = 1.9V
R_fixture = 50Ohm
C_fixture = 0F
|   Time   V(typ)   V(min)   V(max)
0s        1.8V       1.7V       1.9V
650ps     1.8V       1.7V       1.897V
750ps     1.8V       1.7V       1.809V
1.125ns   1.803V     1.7V       1.309V
1.325ns   1.796V     1.7V       1.186V
1.55ns    1.715V     1.7V       1.132V
2.025ns   1.474V     1.701V     1.119V
2.525ns   1.366V     1.702V     1.122V
4.125ns   1.344V     1.533V     1.119V
5.775ns   1.343V     1.502V     1.117V
[Rising Waveform]
V_fixture = 1.8V
V_fixture_min = 1.7V
V_fixture_max = 1.9V
R_fixture = 50Ohm
C_fixture = 0F
|   Time   V(typ)   V(min)   V(max)
0s        1.341V     1.5V       1.115V
500ps     1.341V     1.5V       1.131V
575ps     1.339V     1.5V       1.24V
800ps     1.328V     1.5V       1.716V
1.075ns   1.427V     1.499V     1.877V
1.35ns    1.682V     1.497V     1.895V
1.7ns     1.787V     1.49V      1.895V
2.075ns   1.798V     1.511V     1.895V
2.875ns   1.796V     1.68V      1.896V
4.35ns    1.798V     1.699V     1.898V
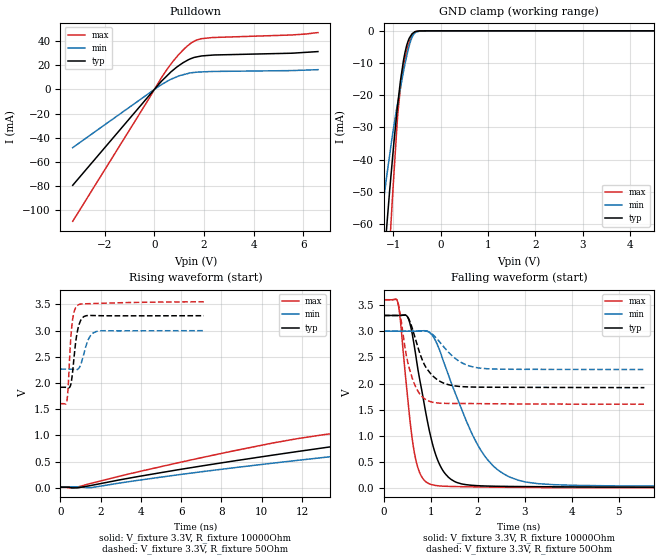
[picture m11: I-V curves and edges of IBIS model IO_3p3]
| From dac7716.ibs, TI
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|   io_3p3 Model
[Model]   IO_3p3
Model_type   I/O_open_drain
Polarity   Non-Inverting
Enable   Active-Low
Vinl = 0.6
Vinh = 2.1
Vmeas = 1.65
Vref = 3.3
Cref = 15pF
Rref = 10000
|   typ   min   max
|   (nom PVT)   (Fast PVT)   (slow PVT)
|Average
C_comp   5.210e-12   4.151e-12   6.231e-12
|ON state : BUFFER OUTPUT TURNED HIGH
|C_comp   5.381e-12   4.314e-12   6.412e-12
|OFF state: BUFFER in HIGH IMPEDANCE for IOs and 3-state,
|This is BUFFER in LOW state for OUTPUT only type
|C_comp   5.040e-12   3.989e-12   6.050e-12
| Where nom  PVT is Nominal Process, 3.3V, 42C
|   Fast PVT is Strong Process,  3.6V, -40C
|   Slow PVT is Weak Process,   3V, 122C
[Voltage Range]   3.3   3   3.6
|Ambient Temperature   25   105   -40
|Junction Temperature
[Temperature Range]   42   122   -40
[Pullup Reference]   3.3   3   3.6
[Pulldown Reference]   0   0   0
[Power Clamp Reference]   3.3   3   3.6
[GND Clamp Reference]   0   0   0
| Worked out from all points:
|   slope of the pulldown table from 0 to 0.495 V, typ, clamps not added: 45.2 ohm
|   GND clamp passes 1 mA (typ) near -0.61 V on its own axis
|   falling waveform, V_fixture 3.3V, R_fixture 10000Ohm: 20-80 % time 433ps typ, 871ps min, 256ps max; typ from 3.3 V to 0.014 V
|   rising waveform, V_fixture 3.3V, R_fixture 10000Ohm: 20-80 % time 148ns typ, 176ns min, 113ns max; typ from 0.013 V to 3.3 V
|   falling waveform, V_fixture 3.3V, R_fixture 50Ohm: 20-80 % time 374ps typ, 494ps min, 277ps max; typ from 3.3 V to 1.92 V
|   rising waveform, V_fixture 3.3V, R_fixture 50Ohm: 20-80 % time 257ps typ, 354ps min, 195ps max; typ from 1.92 V to 3.28 V
[Pulldown]
|   Voltage   I(typ)   I(min)   I(max)
-3.3V     -79.3mA    -48.16mA   -109.1mA
-236.4mV  -5.689mA   -3.511mA   -8.209mA
292.8mV   6.868mA    3.971mA    9.916mA
660mV     14.3mA     8.267mA    20.78mA
973.2mV   19.42mA    10.95mA    28.6mA
1.452V    25.22mA    13.59mA    37.82mA
1.664V    26.62mA    14.1mA     40.46mA
1.873V    27.46mA    14.37mA    41.79mA
2.327V    28.26mA    14.74mA    42.77mA
5.516V    29.83mA    15.47mA    44.9mA
6.6V      31.19mA    16.23mA    46.9mA
[GND Clamp]
|   Voltage   I(typ)   I(min)   I(max)
-3.3V     -529.6mA   -360.1mA   -768.8mA
-1.278V   -86mA      -60.61mA   -124.7mA
-1.14V    -60.35mA   -44.81mA   -83.52mA
-1.079V   -49.33mA   -38.4mA    -66.59mA
-1.035V   -42mA      -33.75mA   -55.2mA
-909.6mV  -22.74mA   -22.26mA   -25.96mA
-819.6mV  -12.26mA   -15.08mA   -13.98mA
-755.7mV  -6.687mA   -10.25mA   -8.629mA
-693mV    -3.267mA   -6.057mA   -4.729mA
-615mV    -1.08mA    -2.267mA   -1.556mA
-547.8mV  -287.7uA   -661.2uA   -372.1uA
6.6V      0A         0A         0A
[POWER Clamp]
|   Voltage   I(typ)   I(min)   I(max)
-3.3V     0A         0A         0A
6.6V      0A         0A         0A
[Ramp]
R_load = 10000
|   typ   min   max
dV/dt_r   1.97204/1.48559e-07   1.78744/1.77544e-07   2.15396/1.1276e-07
dV/dt_f   1.97207/4.32764e-10   1.78798/8.72838e-10   2.15396/2.56007e-10
[Falling Waveform]
V_fixture = 3.3V
V_fixture_min = 3V
V_fixture_max = 3.6V
R_fixture = 10000Ohm
C_fixture = 0F
|   Time   V(typ)   V(min)   V(max)
0s        3.3V       3V         3.6V
300ps     3.3V       3V         3.532V
525ps     3.228V     3V         1.543V
625ps     2.827V     3V         798.9mV
725ps     2.258V     3.002V     387.7mV
1.05ns    794mV      2.895V     64.27mV
1.425ns   174.6mV    2.034V     37.29mV
2.075ns   48.64mV    713.5mV    26.61mV
3.025ns   34.36mV    121.5mV    18.19mV
17.52ns   13.6mV     23.49mV    10.3mV
[Rising Waveform]
V_fixture = 3.3V
V_fixture_min = 3V
V_fixture_max = 3.6V
R_fixture = 10000Ohm
C_fixture = 0F
|   Time   V(typ)   V(min)   V(max)
0s        13.21mV    20.03mV    10.06mV
11.77ns   692.9mV    524.5mV    939.1mV
21.35ns   1.13V      902.9mV    1.269V
32.88ns   1.35V      1.243V     1.481V
46.08ns   1.506V     1.43V      1.715V
120.7ns   2.294V     1.972V     2.869V
171.4ns   2.732V     2.29V      3.339V
242.9ns   3.11V      2.648V     3.531V
340.7ns   3.246V     2.889V     3.586V
639.1ns   3.298V     2.989V     3.6V
[Falling Waveform]
V_fixture = 3.3V
V_fixture_min = 3V
V_fixture_max = 3.6V
R_fixture = 50Ohm
C_fixture = 0F
|   Time   V(typ)   V(min)   V(max)
0s        3.3V       3V         3.6V
275ps     3.3V       3V         3.597V
325ps     3.3V       3V         3.433V
475ps     3.299V     3V         2.54V
575ps     3.129V     3V         2.181V
750ps     2.615V     3.002V     1.818V
950ps     2.241V     2.988V     1.669V
1.3ns     1.999V     2.673V     1.623V
1.975ns   1.933V     2.305V     1.618V
5.55ns    1.923V     2.268V     1.607V
[Rising Waveform]
V_fixture = 3.3V
V_fixture_min = 3V
V_fixture_max = 3.6V
R_fixture = 50Ohm
C_fixture = 0F
|   Time   V(typ)   V(min)   V(max)
0s        1.918V     2.264V     1.605V
325ps     1.915V     2.265V     1.667V
375ps     1.91V      2.265V     1.879V
475ps     1.928V     2.264V     2.617V
575ps     2.115V     2.262V     3.122V
675ps     2.489V     2.258V     3.355V
875ps     3.046V     2.266V     3.488V
1.4ns     3.288V     2.841V     3.513V
1.8ns     3.285V     2.984V     3.517V
7.125ns   3.283V     2.998V     3.549V
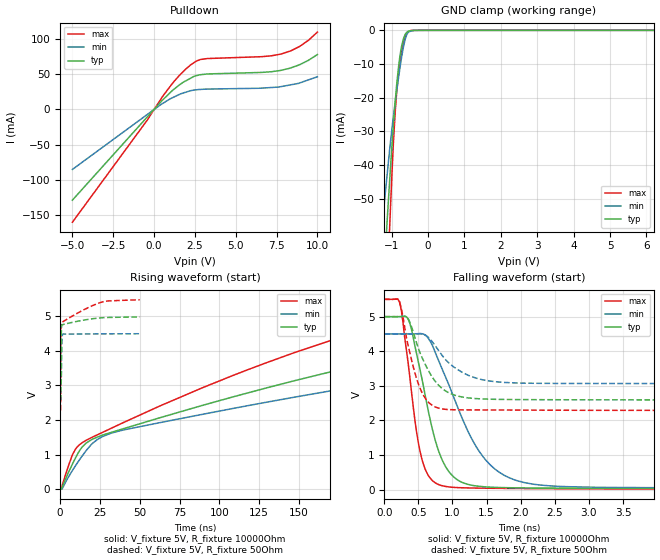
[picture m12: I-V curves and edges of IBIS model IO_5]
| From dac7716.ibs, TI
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|   io_5 Model
[Model]   IO_5
Model_type   I/O_open_drain
Polarity   Non-Inverting
Enable   Active-Low
Vinl = 0.6
Vinh = 2.5
Vmeas = 2.5
Vref = 5
Cref = 15pF
Rref = 10000
|   typ   min   max
|   (nom PVT)   (Fast PVT)   (slow PVT)
|Average
C_comp   4.843e-12   3.910e-12   5.780e-12
|ON state : BUFFER OUTPUT TURNED HIGH
|C_comp   4.951e-12   4.037e-12   5.902e-12
|OFF state: BUFFER in HIGH IMPEDANCE for IOs and 3-state,
|This is BUFFER in LOW state for OUTPUT only type
|C_comp   4.735e-12   3.783e-12   5.659e-12
| Where nom  PVT is Nominal Process, 5V, 42C
|   Fast PVT is Strong Process,  5.5V, -40C
|   Slow PVT is Weak Process,   4.5V, 122C
[Voltage Range]   5   4.5   5.5
|Ambient Temperature   25   105   -40
|Junction Temperature
[Temperature Range]   42   122   -40
[Pullup Reference]   5   4.5   5.5
[Pulldown Reference]   0   0   0
[Power Clamp Reference]   5   4.5   5.5
[GND Clamp Reference]   0   0   0
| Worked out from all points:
|   slope of the pulldown table from 0 to 0.75 V, typ, clamps not added: 40.3 ohm
|   GND clamp passes 1 mA (typ) near -0.61 V on its own axis
|   falling waveform, V_fixture 5V, R_fixture 10000Ohm: 20-80 % time 351ps typ, 638ps min, 224ps max; typ from 5 V to 0.018 V
|   rising waveform, V_fixture 5V, R_fixture 10000Ohm: 20-80 % time 218ns typ, 260ns min, 168ns max; typ from 0.018 V to 5 V
|   falling waveform, V_fixture 5V, R_fixture 50Ohm: 20-80 % time 341ps typ, 457ps min, 239ps max; typ from 5 V to 2.59 V
|   rising waveform, V_fixture 5V, R_fixture 50Ohm: 20-80 % time 246ps typ, 305ps min, 1.32ns max; typ from 2.59 V to 4.98 V
[Pulldown]
|   Voltage   I(typ)   I(min)   I(max)
-5V       -128.9mA   -85.22mA   -160.2mA
-413mV    -10.52mA   -7.085mA   -14.99mA
475mV     12.39mA    7.804mA    16.86mA
1.171V    27.87mA    17.2mA     38.46mA
2.227V    44.3mA     26.66mA    63.08mA
2.612V    48.2mA     28.04mA    69.04mA
3.261V    50.49mA    29mA       72.4mA
6.588V    52.68mA    30.36mA    75.04mA
7.766V    55.59mA    32.47mA    78.76mA
8.926V    63.83mA    37.77mA    89.81mA
9.465V    70.11mA    42.18mA    98.62mA
10V       78.11mA    46.56mA    110mA
[GND Clamp]
|   Voltage   I(typ)   I(min)   I(max)
-5V       -915.8mA   -639.1mA   -1.312A
-1.254V   -81.7mA    -58.09mA   -117.5mA
-1.123V   -57.01mA   -43.1mA    -78.65mA
-1.062V   -46.48mA   -36.61mA   -61.35mA
-1.04V    -42.7mA    -34.25mA   -55.6mA
-946.5mV  -27.93mA   -25.45mA   -32.97mA
-853mV    -15.61mA   -17.64mA   -17.74mA
-798mV    -10.12mA   -13.34mA   -11.93mA
-725mV    -4.786mA   -8.086mA   -6.538mA
-633mV    -1.418mA   -2.978mA   -2.099mA
-540mV    -246.6uA   -560.8uA   -419.3uA
10V       0A         0A         0A
[POWER Clamp]
|   Voltage   I(typ)   I(min)   I(max)
-5V       0A         0A         0A
10V       0A         0A         0A
[Ramp]
R_load = 10000
|   typ   min   max
dV/dt_r   2.98906/2.18221e-07   2.68358/2.62485e-07   3.29123/1.67731e-07
dV/dt_f   2.98914/3.50934e-10   2.68489/6.38064e-10   3.29123/2.24468e-10
[Falling Waveform]
V_fixture = 5V
V_fixture_min = 4.5V
V_fixture_max = 5.5V
R_fixture = 10000Ohm
C_fixture = 0F
|   Time   V(typ)   V(min)   V(max)
0s        5V         4.5V       5.5V
225ps     5.001V     4.5V       5.419V
375ps     4.809V     4.5V       3.252V
475ps     3.918V     4.505V     1.65V
575ps     2.983V     4.495V     730mV
775ps     1.247V     3.833V     167.4mV
975ps     456.1mV    2.891V     74.01mV
1.575ns   70.96mV    678.2mV    40.98mV
2.5ns     44.42mV    102.4mV    27.41mV
25.83ns   18.3mV     26.24mV    14.82mV
[Rising Waveform]
V_fixture = 5V
V_fixture_min = 4.5V
V_fixture_max = 5.5V
R_fixture = 10000Ohm
C_fixture = 0F
|   Time   V(typ)   V(min)   V(max)
0s        18.1mV     25.17mV    14.62mV
10.03ns   938mV      705.9mV    1.185V
16.6ns    1.342V     1.132V     1.42V
32.12ns   1.644V     1.622V     1.763V
145.7ns   3.121V     2.65V      3.927V
237.1ns   4.078V     3.346V     5.12V
305.8ns   4.612V     3.788V     5.407V
364.3ns   4.85V      4.092V     5.465V
469.6ns   4.959V     4.387V     5.494V
684.2ns   4.996V     4.48V      5.5V
[Falling Waveform]
V_fixture = 5V
V_fixture_min = 4.5V
V_fixture_max = 5.5V
R_fixture = 50Ohm
C_fixture = 0F
|   Time   V(typ)   V(min)   V(max)
0s        5V         4.5V       5.5V
225ps     5.001V     4.5V       5.426V
350ps     4.939V     4.5V       4.165V
450ps     4.396V     4.502V     3.37V
550ps     3.832V     4.504V     2.82V
675ps     3.345V     4.342V     2.478V
825ps     2.965V     3.943V     2.342V
1.2ns     2.66V      3.335V     2.305V
1.75ns    2.607V     3.1V       2.302V
7.975ns   2.589V     3.063V     2.29V
[Rising Waveform]
V_fixture = 5V
V_fixture_min = 4.5V
V_fixture_max = 5.5V
R_fixture = 50Ohm
C_fixture = 0F
|   Time   V(typ)   V(min)   V(max)
0s        2.587V     3.06V      2.289V
275ps     2.582V     3.06V      2.343V
325ps     2.581V     3.059V     2.642V
425ps     2.703V     3.056V     3.892V
525ps     3.278V     3.05V      4.598V
750ps     4.524V     3.244V     4.814V
1.125ns   4.747V     4.257V     4.824V
1.725ns   4.761V     4.487V     4.843V
26.15ns   4.958V     4.493V     5.412V
49.98ns   4.983V     4.497V     5.479V
